VERSION 5.7 ;
  NOWIREEXTENSIONATPIN ON ;
  DIVIDERCHAR "/" ;
  BUSBITCHARS "[]" ;
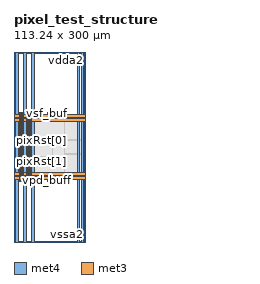
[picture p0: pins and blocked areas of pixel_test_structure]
MACRO pixel_test_structure
  CLASS BLOCK ;
  FOREIGN pixel_test_structure ;
  ORIGIN 0.000 203.855 ;
  SIZE 113.240 BY 300.000 ;
  PIN dac_config_0
    ANTENNAGATEAREA 9.000000 ;
    PORT
      LAYER met4 ;
        RECT 7.930 -107.710 8.660 0.000 ;
    END
  END dac_config_0
  PIN dac_config_1
    ANTENNAGATEAREA 9.000000 ;
    PORT
      LAYER met4 ;
        RECT 9.160 -107.710 9.890 0.000 ;
    END
  END dac_config_1
  PIN dac_config_4
    ANTENNAGATEAREA 2.520000 ;
    PORT
      LAYER met4 ;
        RECT 10.415 -107.710 11.145 0.000 ;
    END
  END dac_config_4
  PIN dac_config_3
    ANTENNAGATEAREA 0.300000 ;
    PORT
      LAYER met4 ;
        RECT 11.645 -107.710 12.375 0.000 ;
    END
  END dac_config_3
  PIN dac_config_5
    ANTENNAGATEAREA 2.520000 ;
    PORT
      LAYER met4 ;
        RECT 12.875 -107.710 13.605 0.000 ;
    END
  END dac_config_5
  PIN dac_config_2
    ANTENNAGATEAREA 9.000000 ;
    PORT
      LAYER met4 ;
        RECT 14.130 -107.710 14.860 0.000 ;
    END
  END dac_config_2
  PIN readOut[0]
    ANTENNADIFFAREA 0.891000 ;
    PORT
      LAYER met4 ;
        RECT 25.425 -107.710 26.205 0.000 ;
    END
  END readOut[0]
  PIN readOut[1]
    ANTENNADIFFAREA 0.891000 ;
    PORT
      LAYER met4 ;
        RECT 26.705 -107.710 27.485 0.000 ;
    END
  END readOut[1]
  PIN vpd_buff
    ANTENNAGATEAREA 38.399998 ;
    ANTENNADIFFAREA 13.040000 ;
    PORT
      LAYER met4 ;
        RECT 52.295 -107.710 53.025 -104.710 ;
    END
  END vpd_buff
  PIN dac_config_7
    ANTENNAGATEAREA 32.000000 ;
    PORT
      LAYER met4 ;
        RECT 65.090 -107.710 66.620 -104.710 ;
    END
    PORT
      LAYER met4 ;
        RECT 65.090 -3.000 66.620 0.000 ;
    END
  END dac_config_7
  PIN vpr_buff
    ANTENNAGATEAREA 38.399998 ;
    ANTENNADIFFAREA 13.040000 ;
    PORT
      LAYER met4 ;
        RECT 78.685 -107.710 79.415 -104.710 ;
    END
  END vpr_buff
  PIN vdiff_buff
    ANTENNAGATEAREA 38.399998 ;
    ANTENNADIFFAREA 13.040000 ;
    PORT
      LAYER met4 ;
        RECT 78.685 -3.000 79.415 0.000 ;
    END
  END vdiff_buff
  PIN vsf_buf
    ANTENNAGATEAREA 38.399998 ;
    ANTENNADIFFAREA 13.040000 ;
    PORT
      LAYER met4 ;
        RECT 52.295 -3.000 53.025 0.000 ;
    END
  END vsf_buf
  PIN vssd2
    ANTENNADIFFAREA 2.373000 ;
    PORT
      LAYER met4 ;
        RECT 15.360 -203.855 19.855 96.145 ;
    END
  END vssd2
  PIN rowReadON[1]
    ANTENNAGATEAREA 0.252000 ;
    PORT
      LAYER met4 ;
        RECT 24.070 -107.710 24.850 0.000 ;
    END
  END rowReadON[1]
  PIN rowReadOFF[1]
    ANTENNAGATEAREA 0.126000 ;
    PORT
      LAYER met4 ;
        RECT 22.840 -107.710 23.570 0.000 ;
    END
  END rowReadOFF[1]
  PIN rowReadOFF[0]
    ANTENNAGATEAREA 0.126000 ;
    PORT
      LAYER met4 ;
        RECT 21.585 -107.710 22.315 0.000 ;
    END
  END rowReadOFF[0]
  PIN rowReadON[0]
    ANTENNAGATEAREA 0.252000 ;
    PORT
      LAYER met4 ;
        RECT 20.355 -107.710 21.085 0.000 ;
    END
  END rowReadON[0]
  PIN vdda2
    ANTENNADIFFAREA 106.722198 ;
    PORT
      LAYER met4 ;
        RECT 106.310 -203.855 110.310 96.145 ;
    END
    PORT
      LAYER met4 ;
        RECT 3.000 -203.855 7.000 96.145 ;
    END
    PORT
      LAYER met3 ;
        RECT 0.000 -6.980 113.240 -3.000 ;
    END
    PORT
      LAYER met3 ;
        RECT 0.000 -104.710 113.240 -100.730 ;
    END
  END vdda2
  PIN vssa2
    ANTENNAGATEAREA 6.400000 ;
    ANTENNADIFFAREA 1154.272583 ;
    PORT
      LAYER met4 ;
        RECT 99.725 -203.855 103.725 96.145 ;
    END
    PORT
      LAYER met4 ;
        RECT 27.985 -203.855 31.985 96.145 ;
    END
    PORT
      LAYER met3 ;
        RECT 0.000 -13.445 113.240 -9.445 ;
    END
    PORT
      LAYER met3 ;
        RECT 0.000 -98.265 113.240 -94.265 ;
    END
  END vssa2
  PIN pixRst[0]
    ANTENNAGATEAREA 0.126000 ;
    PORT
      LAYER met3 ;
        RECT 0.000 -43.235 3.000 -42.635 ;
    END
  END pixRst[0]
  PIN pixRst[1]
    ANTENNAGATEAREA 0.126000 ;
    PORT
      LAYER met3 ;
        RECT 0.000 -65.075 3.000 -64.475 ;
    END
  END pixRst[1]
  OBS
      LAYER nwell ;
        RECT 23.735 -100.350 106.315 -7.360 ;
      LAYER li1 ;
        RECT 23.865 -100.220 106.185 -7.490 ;
      LAYER met1 ;
        RECT 23.225 -100.280 106.245 -7.430 ;
      LAYER met2 ;
        RECT 23.225 -100.015 110.310 -7.695 ;
      LAYER met3 ;
        RECT 3.000 -9.045 110.270 -7.380 ;
        RECT 3.000 -42.235 110.270 -13.845 ;
        RECT 3.400 -43.635 110.270 -42.235 ;
        RECT 3.000 -64.075 110.270 -43.635 ;
        RECT 3.400 -65.475 110.270 -64.075 ;
        RECT 3.000 -93.865 110.270 -65.475 ;
        RECT 3.000 -100.330 110.270 -98.665 ;
      LAYER met4 ;
        RECT 32.385 -3.400 51.895 -3.000 ;
        RECT 53.425 -3.400 64.690 -3.000 ;
        RECT 67.020 -3.400 78.285 -3.000 ;
        RECT 32.385 -104.310 79.415 -3.400 ;
        RECT 32.385 -104.710 51.895 -104.310 ;
        RECT 53.425 -104.710 64.690 -104.310 ;
        RECT 67.020 -104.710 78.285 -104.310 ;
      LAYER met5 ;
        RECT 31.985 -68.545 61.365 -39.165 ;
  END
END pixel_test_structure
END LIBRARY

